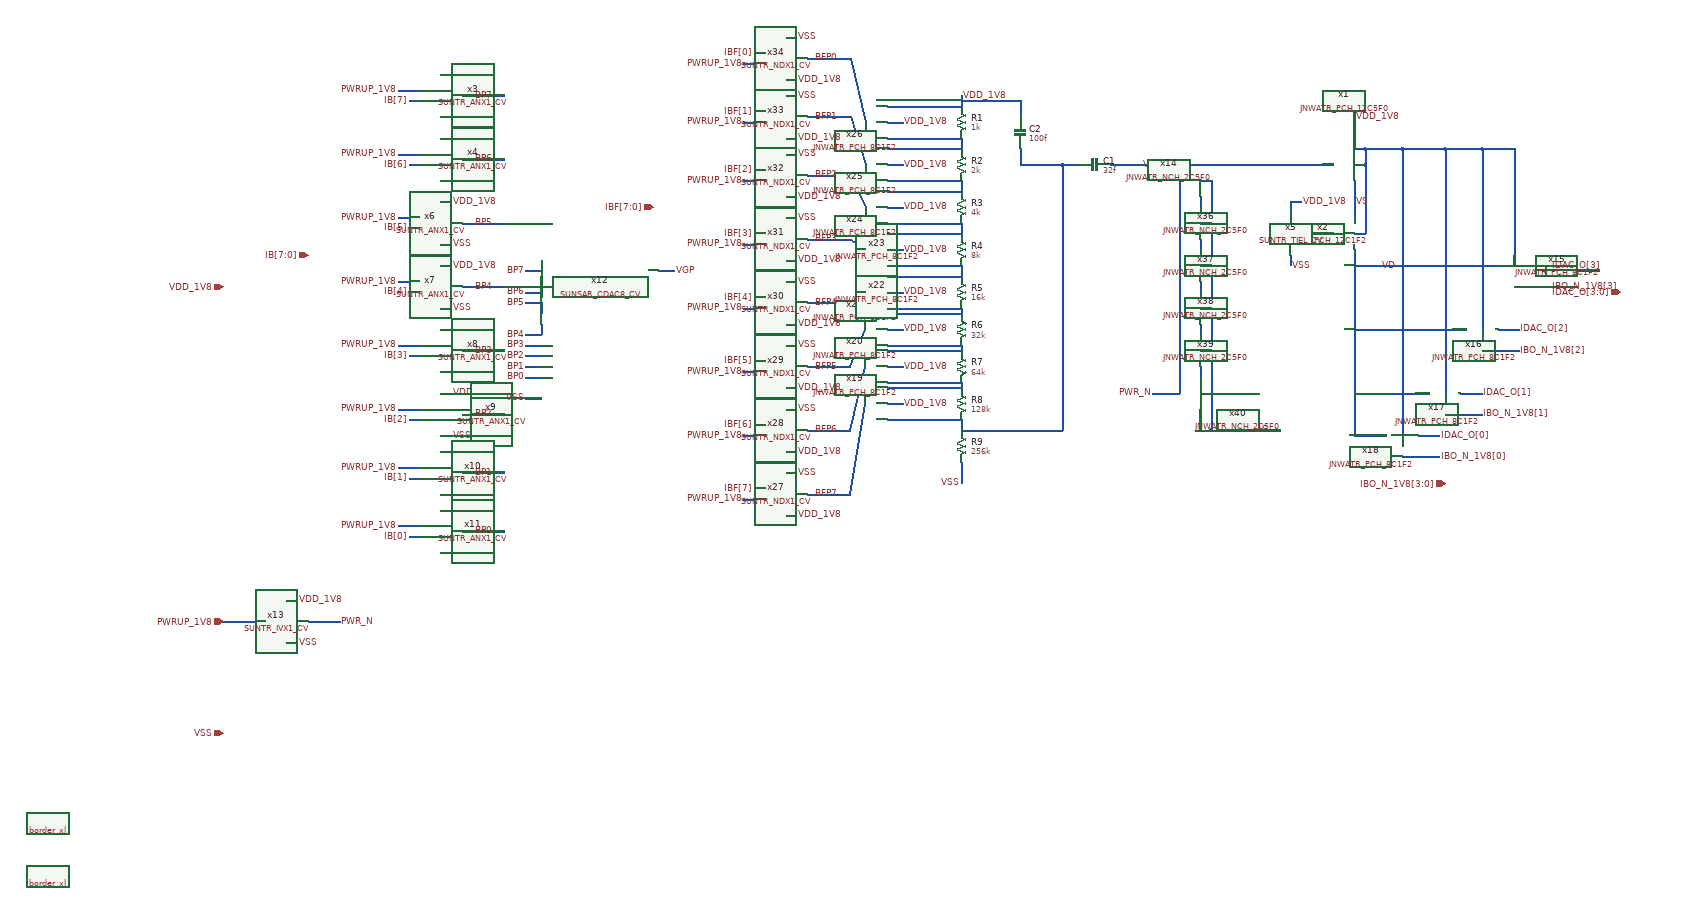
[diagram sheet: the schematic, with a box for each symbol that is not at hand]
v {xschem version=3.4.5 file_version=1.2
}
G {}
K {}
V {}
S {}
E {}
N 2300 -1210 2300 -1140 {
lab=VS}
N 2300 -1110 2320 -1110 {
lab=VDD_1V8}
N 2320 -1240 2320 -1110 {
lab=VDD_1V8}
N 2300 -1240 2320 -1240 {
lab=VDD_1V8}
N 2320 -1270 2320 -1240 {
lab=VDD_1V8}
N 2300 -1270 2320 -1270 {
lab=VDD_1V8}
N 2300 -1330 2300 -1270 {
lab=VDD_1V8}
N 1930 -1240 2260 -1240 {
lab=VGP}
N 580 -1410 600 -1410 {
lab=VDD_1V8}
N 580 -1330 600 -1330 {
lab=VSS}
N 520 -1360 540 -1360 {
lab=IB[7]}
N 580 -1290 600 -1290 {
lab=VDD_1V8}
N 580 -1210 600 -1210 {
lab=VSS}
N 520 -1240 540 -1240 {
lab=IB[6]}
N 580 -1170 600 -1170 {
lab=VDD_1V8}
N 580 -1090 600 -1090 {
lab=VSS}
N 520 -1120 540 -1120 {
lab=IB[5]}
N 580 -1050 600 -1050 {
lab=VDD_1V8}
N 580 -970 600 -970 {
lab=VSS}
N 520 -1000 540 -1000 {
lab=IB[4]}
N 580 -930 600 -930 {
lab=VDD_1V8}
N 580 -850 600 -850 {
lab=VSS}
N 520 -880 540 -880 {
lab=IB[3]}
N 580 -730 600 -730 {
lab=VSS}
N 520 -760 540 -760 {
lab=IB[2]}
N 580 -700 600 -700 {
lab=VDD_1V8}
N 580 -620 600 -620 {
lab=VSS}
N 520 -650 540 -650 {
lab=IB[1]}
N 580 -590 600 -590 {
lab=VDD_1V8}
N 580 -510 600 -510 {
lab=VSS}
N 520 -540 540 -540 {
lab=IB[0]}
N 620 -1370 700 -1370 {
lab=BP7}
N 620 -1250 700 -1250 {
lab=BP6}
N 620 -1130 700 -1130 {
lab=BP5}
N 620 -1010 700 -1010 {
lab=BP4}
N 620 -890 700 -890 {
lab=BP3}
N 620 -770 700 -770 {
lab=BP2}
N 620 -660 700 -660 {
lab=BP1}
N 620 -550 700 -550 {
lab=BP0}
N 1840 -1240 1930 -1240 {
lab=VGP}
N 2300 -1080 2300 -900 {
lab=VD}
N 290 -420 310 -420 {
lab=VDD_1V8}
N 290 -340 310 -340 {
lab=VSS}
N 230 -380 250 -380 {
lab=PWRUP_1V8}
N 170 -380 230 -380 {
lab=PWRUP_1V8}
N 330 -380 390 -380 {
lab=PWR_N}
N 2000 -740 2030 -740 {
lab=VSS}
N 2030 -740 2160 -740 {
lab=VSS}
N 2390 -1270 2390 -730 {
lab=VDD_1V8}
N 2320 -1270 2390 -1270 {
lab=VDD_1V8}
N 2470 -1270 2470 -810 {
lab=VDD_1V8}
N 2390 -1270 2470 -1270 {
lab=VDD_1V8}
N 2470 -1270 2540 -1270 {
lab=VDD_1V8}
N 2600 -1270 2600 -1050 {
lab=VDD_1V8}
N 2540 -1270 2600 -1270 {
lab=VDD_1V8}
N 2300 -1050 2570 -1050 {
lab=VD}
N 2300 -900 2300 -730 {
lab=VD}
N 2300 -730 2360 -730 {
lab=VD}
N 2300 -810 2440 -810 {
lab=VD}
N 2300 -930 2510 -930 {
lab=VD}
N 2540 -1270 2540 -930 {
lab=VDD_1V8}
N 2630 -1050 2670 -1050 {
lab=IDAC_O[3]}
N 2570 -930 2610 -930 {
lab=IDAC_O[2]}
N 2500 -810 2540 -810 {
lab=IDAC_O[1]}
N 2420 -730 2460 -730 {
lab=IDAC_O[0]}
N 2390 -690 2460 -690 {
lab=IBN_1V8[0]}
N 2470 -770 2540 -770 {
lab=IBN_1V8[1]}
N 2540 -890 2610 -890 {
lab=IBN_1V8[2]}
N 2600 -1010 2670 -1010 {
lab=IBN_1V8[3]}
N 580 -810 600 -810 {
lab=VDD_1V8}
N 500 -1380 540 -1380 {
lab=PWRUP_1V8}
N 500 -1260 540 -1260 {
lab=PWRUP_1V8}
N 500 -1140 540 -1140 {
lab=PWRUP_1V8}
N 500 -1020 540 -1020 {
lab=PWRUP_1V8}
N 500 -900 540 -900 {
lab=PWRUP_1V8}
N 500 -780 540 -780 {
lab=PWRUP_1V8}
N 500 -670 540 -670 {
lab=PWRUP_1V8}
N 500 -560 540 -560 {
lab=PWRUP_1V8}
N 740 -840 770 -840 {
lab=BP0}
N 740 -860 770 -860 {
lab=BP1}
N 740 -880 770 -880 {
lab=BP2}
N 740 -900 770 -900 {
lab=BP3}
N 740 -920 770 -920 {
lab=BP4}
N 740 -980 770 -980 {
lab=BP5}
N 740 -1000 770 -1000 {
lab=BP6}
N 770 -980 770 -960 {
lab=BP5}
N 740 -1040 770 -1040 {
lab=BP7}
N 770 -1020 770 -1000 {
lab=BP6}
N 990 -1040 1020 -1040 {
lab=VGP}
N 740 -800 770 -800 {
lab=VSS}
N 770 -1060 770 -1040 {
lab=BP7}
N 770 -940 770 -920 {
lab=BP4}
N 1560 -1290 1560 -1270 {
lab=#net2}
N 1560 -1210 1560 -1190 {
lab=#net3}
N 1560 -1130 1560 -1110 {
lab=#net4}
N 1560 -1050 1560 -1030 {
lab=#net5}
N 1560 -970 1560 -960 {
lab=#net6}
N 1560 -900 1560 -890 {
lab=#net7}
N 1560 -830 1560 -820 {
lab=#net8}
N 1560 -760 1560 -740 {
lab=#net9}
N 1750 -1240 1780 -1240 {
lab=#net9}
N 1750 -1240 1750 -740 {
lab=#net9}
N 1560 -740 1750 -740 {
lab=#net9}
N 1560 -680 1560 -640 {
lab=VSS}
N 1560 -1370 1560 -1350 {
lab=VDD_1V8}
N 1670 -1360 1670 -1330 {
lab=VDD_1V8}
N 1560 -1360 1670 -1360 {
lab=VDD_1V8}
N 1670 -1270 1670 -1240 {
lab=#net9}
N 1670 -1240 1750 -1240 {
lab=#net9}
N 1420 -790 1450 -790 {
lab=VDD_1V8}
N 1420 -820 1560 -820 {
lab=#net8}
N 1430 -760 1560 -760 {
lab=#net9}
N 1420 -760 1430 -760 {
lab=#net9}
N 1420 -860 1450 -860 {
lab=VDD_1V8}
N 1420 -890 1560 -890 {
lab=#net8}
N 1430 -830 1560 -830 {
lab=#net9}
N 1420 -830 1430 -830 {
lab=#net9}
N 1420 -930 1450 -930 {
lab=VDD_1V8}
N 1420 -960 1560 -960 {
lab=#net8}
N 1430 -900 1560 -900 {
lab=#net9}
N 1420 -900 1430 -900 {
lab=#net9}
N 1420 -1000 1450 -1000 {
lab=VDD_1V8}
N 1420 -1030 1560 -1030 {
lab=#net8}
N 1430 -970 1560 -970 {
lab=#net9}
N 1420 -970 1430 -970 {
lab=#net9}
N 1420 -1080 1450 -1080 {
lab=VDD_1V8}
N 1420 -1110 1560 -1110 {
lab=#net8}
N 1430 -1050 1560 -1050 {
lab=#net9}
N 1420 -1050 1430 -1050 {
lab=#net9}
N 1420 -1160 1450 -1160 {
lab=VDD_1V8}
N 1420 -1190 1560 -1190 {
lab=#net8}
N 1430 -1130 1560 -1130 {
lab=#net9}
N 1420 -1130 1430 -1130 {
lab=#net9}
N 1420 -1240 1450 -1240 {
lab=VDD_1V8}
N 1420 -1270 1560 -1270 {
lab=#net8}
N 1430 -1210 1560 -1210 {
lab=#net9}
N 1420 -1210 1430 -1210 {
lab=#net9}
N 1420 -1320 1450 -1320 {
lab=VDD_1V8}
N 1420 -1350 1560 -1350 {
lab=#net8}
N 1430 -1290 1560 -1290 {
lab=#net9}
N 1420 -1290 1430 -1290 {
lab=#net9}
N 1230 -580 1250 -580 {
lab=VDD_1V8}
N 1230 -660 1250 -660 {
lab=VSS}
N 1170 -630 1190 -630 {
lab=IB[7]}
N 1230 -700 1250 -700 {
lab=VDD_1V8}
N 1230 -780 1250 -780 {
lab=VSS}
N 1170 -750 1190 -750 {
lab=IB[6]}
N 1230 -820 1250 -820 {
lab=VDD_1V8}
N 1230 -900 1250 -900 {
lab=VSS}
N 1170 -870 1190 -870 {
lab=IB[5]}
N 1230 -940 1250 -940 {
lab=VDD_1V8}
N 1230 -1020 1250 -1020 {
lab=VSS}
N 1170 -990 1190 -990 {
lab=IB[4]}
N 1230 -1060 1250 -1060 {
lab=VDD_1V8}
N 1230 -1140 1250 -1140 {
lab=VSS}
N 1170 -1110 1190 -1110 {
lab=IB[3]}
N 1230 -1260 1250 -1260 {
lab=VSS}
N 1170 -1230 1190 -1230 {
lab=IB[2]}
N 1230 -1290 1250 -1290 {
lab=VDD_1V8}
N 1230 -1370 1250 -1370 {
lab=VSS}
N 1170 -1340 1190 -1340 {
lab=IB[1]}
N 1230 -1400 1250 -1400 {
lab=VDD_1V8}
N 1230 -1480 1250 -1480 {
lab=VSS}
N 1170 -1450 1190 -1450 {
lab=IB[0]}
N 1270 -620 1350 -620 {
lab=BP7}
N 1270 -740 1350 -740 {
lab=BP6}
N 1270 -860 1350 -860 {
lab=BP5}
N 1270 -980 1350 -980 {
lab=BP4}
N 1270 -1100 1350 -1100 {
lab=BP3}
N 1270 -1220 1350 -1220 {
lab=BP2}
N 1270 -1330 1350 -1330 {
lab=BP1}
N 1270 -1440 1350 -1440 {
lab=BP0}
N 1230 -1180 1250 -1180 {
lab=VDD_1V8}
N 1150 -610 1190 -610 {
lab=PWRUP_1V8}
N 1150 -730 1190 -730 {
lab=PWRUP_1V8}
N 1150 -850 1190 -850 {
lab=PWRUP_1V8}
N 1150 -970 1190 -970 {
lab=PWRUP_1V8}
N 1150 -1090 1190 -1090 {
lab=PWRUP_1V8}
N 1150 -1210 1190 -1210 {
lab=PWRUP_1V8}
N 1150 -1320 1190 -1320 {
lab=PWRUP_1V8}
N 1150 -1430 1190 -1430 {
lab=PWRUP_1V8}
N 1350 -1440 1380 -1320 {}
N 1350 -1330 1380 -1240 {}
N 1350 -1220 1380 -1160 {}
N 1350 -1100 1380 -1080 {}
N 1350 -980 1380 -1000 {}
N 1350 -860 1380 -930 {}
N 1350 -740 1380 -860 {}
N 1350 -620 1380 -790 {}
N 2660 -1040 2760 -1040 {}
N 2660 -1050 2660 -1040 {}
N 2300 -1340 2300 -1330 {}
N 2010 -780 2010 -740 {}
N 2010 -860 2010 -840 {}
N 2010 -940 2010 -920 {}
N 2010 -1020 2010 -1000 {}
N 2010 -1100 2010 -1080 {}
N 2010 -1180 2010 -1160 {}
N 2010 -1210 2030 -1210 {}
N 2030 -1210 2030 -740 {}
N 2010 -810 2030 -810 {}
N 2010 -890 2030 -890 {}
N 2010 -970 2030 -970 {}
N 2010 -1130 2030 -1130 {}
N 1970 -1210 1970 -810 {}
N 1920 -810 1970 -810 {}
N 2010 -1050 2030 -1050 {}
N 2220 -1110 2260 -1110 {}
N 2180 -1170 2180 -1150 {}
N 2180 -1170 2200 -1170 {}
N 2180 -1070 2180 -1050 {}
C {devices/ipin.sym} 170 -1010 0 0 {name=p1 lab=VDD_1V8}
C {devices/ipin.sym} 170 -170 0 0 {name=p2 lab=VSS}
C {devices/ipin.sym} 170 -380 0 0 {name=p3 lab=PWRUP_1V8}
C {JNW_ATR_SKY130NM/JNWATR_PCH_12C5F0.sym} 2260 -1240 0 0 {name=x1 }
C {JNW_ATR_SKY130NM/JNWATR_PCH_12C1F2.sym} 2260 -1110 0 0 {name=x2 }
C {devices/lab_wire.sym} 600 -1410 0 1 {name=p4 sig_type=std_logic lab=VDD_1V8}
C {devices/lab_wire.sym} 600 -1330 0 1 {name=p5 sig_type=std_logic lab=VSS}
C {devices/lab_wire.sym} 520 -1360 0 0 {name=p6 sig_type=std_logic lab=IB[7]}
C {devices/lab_wire.sym} 600 -1290 0 1 {name=p7 sig_type=std_logic lab=VDD_1V8}
C {devices/lab_wire.sym} 600 -1210 0 1 {name=p8 sig_type=std_logic lab=VSS}
C {devices/lab_wire.sym} 520 -1240 0 0 {name=p9 sig_type=std_logic lab=IB[6]}
C {devices/lab_wire.sym} 600 -1170 0 1 {name=p10 sig_type=std_logic lab=VDD_1V8}
C {devices/lab_wire.sym} 600 -1090 0 1 {name=p11 sig_type=std_logic lab=VSS}
C {devices/lab_wire.sym} 520 -1120 0 0 {name=p12 sig_type=std_logic lab=IB[5]}
C {devices/lab_wire.sym} 600 -1050 0 1 {name=p13 sig_type=std_logic lab=VDD_1V8}
C {devices/lab_wire.sym} 600 -970 0 1 {name=p14 sig_type=std_logic lab=VSS}
C {devices/lab_wire.sym} 520 -1000 0 0 {name=p15 sig_type=std_logic lab=IB[4]}
C {devices/lab_wire.sym} 600 -930 0 1 {name=p16 sig_type=std_logic lab=VDD_1V8}
C {devices/lab_wire.sym} 600 -850 0 1 {name=p17 sig_type=std_logic lab=VSS}
C {devices/lab_wire.sym} 520 -880 0 0 {name=p18 sig_type=std_logic lab=IB[3]}
C {devices/lab_wire.sym} 600 -810 0 1 {name=p19 sig_type=std_logic lab=VDD_1V8}
C {devices/lab_wire.sym} 600 -730 0 1 {name=p20 sig_type=std_logic lab=VSS}
C {devices/lab_wire.sym} 520 -760 0 0 {name=p21 sig_type=std_logic lab=IB[2]}
C {devices/lab_wire.sym} 600 -700 0 1 {name=p22 sig_type=std_logic lab=VDD_1V8}
C {devices/lab_wire.sym} 600 -620 0 1 {name=p23 sig_type=std_logic lab=VSS}
C {devices/lab_wire.sym} 520 -650 0 0 {name=p24 sig_type=std_logic lab=IB[1]}
C {devices/lab_wire.sym} 600 -590 0 1 {name=p25 sig_type=std_logic lab=VDD_1V8}
C {devices/lab_wire.sym} 600 -510 0 1 {name=p26 sig_type=std_logic lab=VSS}
C {devices/lab_wire.sym} 520 -540 0 0 {name=p27 sig_type=std_logic lab=IB[0]}
C {devices/lab_wire.sym} 2300 -1330 0 1 {name=p28 sig_type=std_logic lab=VDD_1V8}
C {SUN_TR_SKY130NM/SUNTR_IVX1_CV.sym} 250 -380 0 0 {name=x13 }
C {devices/lab_wire.sym} 310 -420 0 1 {name=p29 sig_type=std_logic lab=VDD_1V8}
C {devices/lab_wire.sym} 310 -340 0 1 {name=p30 sig_type=std_logic lab=VSS}
C {devices/lab_wire.sym} 2100 -740 0 1 {name=p31 sig_type=std_logic lab=VSS}
C {devices/lab_wire.sym} 390 -380 0 1 {name=p33 sig_type=std_logic lab=PWR_N}
C {devices/iopin.sym} 2800 -1000 0 0 {name=p35 lab=IDAC_O[3:0]}
C {JNW_ATR_SKY130NM/JNWATR_PCH_8C1F2.sym} 2600 -1010 3 0 {name=x15 }
C {JNW_ATR_SKY130NM/JNWATR_PCH_8C1F2.sym} 2540 -890 3 0 {name=x16 }
C {JNW_ATR_SKY130NM/JNWATR_PCH_8C1F2.sym} 2470 -770 3 0 {name=x17 }
C {JNW_ATR_SKY130NM/JNWATR_PCH_8C1F2.sym} 2390 -690 3 0 {name=x18 }
C {devices/lab_wire.sym} 2460 -730 0 1 {name=p36 sig_type=std_logic lab=IDAC_O[0]}
C {devices/lab_wire.sym} 2540 -810 0 1 {name=p37 sig_type=std_logic lab=IDAC_O[1]}
C {devices/lab_wire.sym} 2610 -930 0 1 {name=p38 sig_type=std_logic lab=IDAC_O[2]}
C {devices/lab_wire.sym} 2670 -1050 0 1 {name=p39 sig_type=std_logic lab=IDAC_O[3]}
C {devices/lab_wire.sym} 2460 -690 0 1 {name=p40 sig_type=std_logic lab=IBO_N_1V8[0]}
C {devices/lab_wire.sym} 2540 -770 0 1 {name=p41 sig_type=std_logic lab=IBO_N_1V8[1]}
C {devices/lab_wire.sym} 2610 -890 0 1 {name=p42 sig_type=std_logic lab=IBO_N_1V8[2]}
C {devices/lab_wire.sym} 2670 -1010 0 1 {name=p43 sig_type=std_logic lab=IBO_N_1V8[3]}
C {devices/ipin.sym} 330 -1070 0 0 {name=p44 lab=IB[7:0]}
C {devices/ipin.sym} 2470 -640 0 0 {name=p45 lab=IBO_N_1V8[3:0]}
C {devices/lab_wire.sym} 2300 -1170 0 1 {name=p47 sig_type=std_logic lab=VS}
C {devices/lab_wire.sym} 2350 -1050 0 1 {name=p48 sig_type=std_logic lab=VD}
C {devices/lab_wire.sym} 1900 -1240 0 1 {name=p49 sig_type=std_logic lab=VGP}
C {SUN_TR_SKY130NM/SUNTR_ANX1_CV.sym} 540 -1360 0 0 {name=x3 }
C {SUN_TR_SKY130NM/SUNTR_ANX1_CV.sym} 540 -1240 0 0 {name=x4 }
C {SUN_TR_SKY130NM/SUNTR_ANX1_CV.sym} 540 -1120 0 0 {name=x6 }
C {SUN_TR_SKY130NM/SUNTR_ANX1_CV.sym} 540 -1000 0 0 {name=x7 }
C {SUN_TR_SKY130NM/SUNTR_ANX1_CV.sym} 540 -880 0 0 {name=x8 }
C {SUN_TR_SKY130NM/SUNTR_ANX1_CV.sym} 540 -760 0 0 {name=x9 }
C {SUN_TR_SKY130NM/SUNTR_ANX1_CV.sym} 540 -650 0 0 {name=x10 }
C {SUN_TR_SKY130NM/SUNTR_ANX1_CV.sym} 540 -540 0 0 {name=x11 }
C {devices/lab_wire.sym} 500 -1380 0 0 {name=p50 sig_type=std_logic lab=PWRUP_1V8}
C {devices/lab_wire.sym} 500 -1260 0 0 {name=p51 sig_type=std_logic lab=PWRUP_1V8}
C {devices/lab_wire.sym} 500 -1140 0 0 {name=p52 sig_type=std_logic lab=PWRUP_1V8}
C {devices/lab_wire.sym} 500 -1020 0 0 {name=p53 sig_type=std_logic lab=PWRUP_1V8}
C {devices/lab_wire.sym} 500 -900 0 0 {name=p54 sig_type=std_logic lab=PWRUP_1V8}
C {devices/lab_wire.sym} 500 -780 0 0 {name=p55 sig_type=std_logic lab=PWRUP_1V8}
C {devices/lab_wire.sym} 500 -670 0 0 {name=p56 sig_type=std_logic lab=PWRUP_1V8}
C {devices/lab_wire.sym} 500 -560 0 0 {name=p57 sig_type=std_logic lab=PWRUP_1V8}
C {devices/lab_wire.sym} 680 -1370 0 0 {name=p58 sig_type=std_logic lab=BP7
}
C {devices/lab_wire.sym} 680 -1250 0 0 {name=p59 sig_type=std_logic lab=BP6
}
C {devices/lab_wire.sym} 680 -1130 0 0 {name=p60 sig_type=std_logic lab=BP5
}
C {devices/lab_wire.sym} 680 -1010 0 0 {name=p61 sig_type=std_logic lab=BP4
}
C {devices/lab_wire.sym} 680 -890 0 0 {name=p62 sig_type=std_logic lab=BP3
}
C {devices/lab_wire.sym} 680 -770 0 0 {name=p63 sig_type=std_logic lab=BP2
}
C {devices/lab_wire.sym} 680 -660 0 0 {name=p64 sig_type=std_logic lab=BP1
}
C {devices/lab_wire.sym} 680 -550 0 0 {name=p65 sig_type=std_logic lab=BP0
}
C {devices/lab_wire.sym} 740 -840 0 0 {name=p46 sig_type=std_logic lab=BP0
}
C {devices/lab_wire.sym} 740 -860 0 0 {name=p66 sig_type=std_logic lab=BP1
}
C {devices/lab_wire.sym} 740 -880 0 0 {name=p67 sig_type=std_logic lab=BP2
}
C {devices/lab_wire.sym} 740 -900 0 0 {name=p68 sig_type=std_logic lab=BP3
}
C {devices/lab_wire.sym} 740 -920 0 0 {name=p69 sig_type=std_logic lab=BP4
}
C {devices/lab_wire.sym} 740 -980 0 0 {name=p70 sig_type=std_logic lab=BP5
}
C {devices/lab_wire.sym} 740 -1000 0 0 {name=p71 sig_type=std_logic lab=BP6
}
C {devices/lab_wire.sym} 740 -1040 0 0 {name=p72 sig_type=std_logic lab=BP7
}
C {devices/lab_wire.sym} 1020 -1040 0 1 {name=p73 sig_type=std_logic lab=VGP
}
C {devices/lab_wire.sym} 740 -800 0 0 {name=p74 sig_type=std_logic lab=VSS
}
C {SUN_SAR9B_SKY130NM/SUNSAR_CDAC8_CV.sym} 790 -1060 0 0 {name=x12}
C {devices/res.sym} 1560 -1320 0 0 {name=R1
value=1k
footprint=1206
device=resistor
m=1}
C {devices/res.sym} 1560 -1240 0 0 {name=R2
value=2k
footprint=1206
device=resistor
m=1}
C {devices/res.sym} 1560 -1160 0 0 {name=R3
value=4k
footprint=1206
device=resistor
m=1}
C {devices/res.sym} 1560 -1080 0 0 {name=R4
value=8k
footprint=1206
device=resistor
m=1}
C {devices/res.sym} 1560 -1000 0 0 {name=R5
value=16k
footprint=1206
device=resistor
m=1}
C {devices/res.sym} 1560 -930 0 0 {name=R6
value=32k
footprint=1206
device=resistor
m=1}
C {devices/res.sym} 1560 -860 0 0 {name=R7
value=64k
footprint=1206
device=resistor
m=1}
C {devices/res.sym} 1560 -790 0 0 {name=R8
value=128k
footprint=1206
device=resistor
m=1}
C {devices/res.sym} 1560 -710 0 0 {name=R9
value=256k
footprint=1206
device=resistor
m=1}
C {devices/lab_wire.sym} 1560 -640 0 0 {name=p32 sig_type=std_logic lab=VSS}
C {devices/lab_wire.sym} 1560 -1370 0 1 {name=p75 sig_type=std_logic lab=VDD_1V8}
C {devices/capa.sym} 1670 -1300 0 0 {name=C2
m=1
value=100f
footprint=1206
device="ceramic capacitor"}
C {JNW_ATR_SKY130NM/JNWATR_PCH_8C1F2.sym} 1380 -790 0 0 {name=x19 }
C {devices/lab_wire.sym} 1450 -790 0 1 {name=p76 sig_type=std_logic lab=VDD_1V8}
C {JNW_ATR_SKY130NM/JNWATR_PCH_8C1F2.sym} 1380 -860 0 0 {name=x20 }
C {devices/lab_wire.sym} 1450 -860 0 1 {name=p77 sig_type=std_logic lab=VDD_1V8}
C {JNW_ATR_SKY130NM/JNWATR_PCH_8C1F2.sym} 1380 -930 0 0 {name=x21 }
C {devices/lab_wire.sym} 1450 -930 0 1 {name=p78 sig_type=std_logic lab=VDD_1V8}
C {JNW_ATR_SKY130NM/JNWATR_PCH_8C1F2.sym} 1380 -1000 0 0 {name=x22 }
C {devices/lab_wire.sym} 1450 -1000 0 1 {name=p79 sig_type=std_logic lab=VDD_1V8}
C {JNW_ATR_SKY130NM/JNWATR_PCH_8C1F2.sym} 1380 -1080 0 0 {name=x23 }
C {devices/lab_wire.sym} 1450 -1080 0 1 {name=p80 sig_type=std_logic lab=VDD_1V8}
C {JNW_ATR_SKY130NM/JNWATR_PCH_8C1F2.sym} 1380 -1160 0 0 {name=x24 }
C {devices/lab_wire.sym} 1450 -1160 0 1 {name=p81 sig_type=std_logic lab=VDD_1V8}
C {JNW_ATR_SKY130NM/JNWATR_PCH_8C1F2.sym} 1380 -1240 0 0 {name=x25 }
C {devices/lab_wire.sym} 1450 -1240 0 1 {name=p82 sig_type=std_logic lab=VDD_1V8}
C {JNW_ATR_SKY130NM/JNWATR_PCH_8C1F2.sym} 1380 -1320 0 0 {name=x26 }
C {devices/lab_wire.sym} 1450 -1320 0 1 {name=p83 sig_type=std_logic lab=VDD_1V8}
C {devices/lab_wire.sym} 1250 -580 2 0 {name=p84 sig_type=std_logic lab=VDD_1V8}
C {devices/lab_wire.sym} 1250 -660 2 0 {name=p85 sig_type=std_logic lab=VSS}
C {devices/lab_wire.sym} 1170 -630 2 1 {name=p86 sig_type=std_logic lab=IBF[7]}
C {devices/lab_wire.sym} 1250 -700 2 0 {name=p87 sig_type=std_logic lab=VDD_1V8}
C {devices/lab_wire.sym} 1250 -780 2 0 {name=p88 sig_type=std_logic lab=VSS}
C {devices/lab_wire.sym} 1170 -750 2 1 {name=p89 sig_type=std_logic lab=IBF[6]}
C {devices/lab_wire.sym} 1250 -820 2 0 {name=p90 sig_type=std_logic lab=VDD_1V8}
C {devices/lab_wire.sym} 1250 -900 2 0 {name=p91 sig_type=std_logic lab=VSS}
C {devices/lab_wire.sym} 1170 -870 2 1 {name=p92 sig_type=std_logic lab=IBF[5]}
C {devices/lab_wire.sym} 1250 -940 2 0 {name=p93 sig_type=std_logic lab=VDD_1V8}
C {devices/lab_wire.sym} 1250 -1020 2 0 {name=p94 sig_type=std_logic lab=VSS}
C {devices/lab_wire.sym} 1170 -990 2 1 {name=p95 sig_type=std_logic lab=IBF[4]}
C {devices/lab_wire.sym} 1250 -1060 2 0 {name=p96 sig_type=std_logic lab=VDD_1V8}
C {devices/lab_wire.sym} 1250 -1140 2 0 {name=p97 sig_type=std_logic lab=VSS}
C {devices/lab_wire.sym} 1170 -1110 2 1 {name=p98 sig_type=std_logic lab=IBF[3]}
C {devices/lab_wire.sym} 1250 -1180 2 0 {name=p99 sig_type=std_logic lab=VDD_1V8}
C {devices/lab_wire.sym} 1250 -1260 2 0 {name=p100 sig_type=std_logic lab=VSS}
C {devices/lab_wire.sym} 1170 -1230 2 1 {name=p101 sig_type=std_logic lab=IBF[2]}
C {devices/lab_wire.sym} 1250 -1290 2 0 {name=p102 sig_type=std_logic lab=VDD_1V8}
C {devices/lab_wire.sym} 1250 -1370 2 0 {name=p103 sig_type=std_logic lab=VSS}
C {devices/lab_wire.sym} 1170 -1340 2 1 {name=p104 sig_type=std_logic lab=IBF[1]}
C {devices/lab_wire.sym} 1250 -1400 2 0 {name=p105 sig_type=std_logic lab=VDD_1V8}
C {devices/lab_wire.sym} 1250 -1480 2 0 {name=p106 sig_type=std_logic lab=VSS}
C {devices/lab_wire.sym} 1170 -1450 2 1 {name=p107 sig_type=std_logic lab=IBF[0]}
C {SUN_TR_SKY130NM/SUNTR_NDX1_CV.sym} 1190 -630 2 1 {name=x27 }
C {SUN_TR_SKY130NM/SUNTR_NDX1_CV.sym} 1190 -750 2 1 {name=x28 }
C {SUN_TR_SKY130NM/SUNTR_NDX1_CV.sym} 1190 -870 2 1 {name=x29 }
C {SUN_TR_SKY130NM/SUNTR_NDX1_CV.sym} 1190 -990 2 1 {name=x30 }
C {SUN_TR_SKY130NM/SUNTR_NDX1_CV.sym} 1190 -1110 2 1 {name=x31 }
C {SUN_TR_SKY130NM/SUNTR_NDX1_CV.sym} 1190 -1230 2 1 {name=x32 }
C {SUN_TR_SKY130NM/SUNTR_NDX1_CV.sym} 1190 -1340 2 1 {name=x33 }
C {SUN_TR_SKY130NM/SUNTR_NDX1_CV.sym} 1190 -1450 2 1 {name=x34 }
C {devices/lab_wire.sym} 1150 -610 2 1 {name=p108 sig_type=std_logic lab=PWRUP_1V8}
C {devices/lab_wire.sym} 1150 -730 2 1 {name=p109 sig_type=std_logic lab=PWRUP_1V8}
C {devices/lab_wire.sym} 1150 -850 2 1 {name=p110 sig_type=std_logic lab=PWRUP_1V8}
C {devices/lab_wire.sym} 1150 -970 2 1 {name=p111 sig_type=std_logic lab=PWRUP_1V8}
C {devices/lab_wire.sym} 1150 -1090 2 1 {name=p112 sig_type=std_logic lab=PWRUP_1V8}
C {devices/lab_wire.sym} 1150 -1210 2 1 {name=p113 sig_type=std_logic lab=PWRUP_1V8}
C {devices/lab_wire.sym} 1150 -1320 2 1 {name=p114 sig_type=std_logic lab=PWRUP_1V8}
C {devices/lab_wire.sym} 1150 -1430 2 1 {name=p115 sig_type=std_logic lab=PWRUP_1V8}
C {devices/lab_wire.sym} 1330 -620 2 1 {name=p116 sig_type=std_logic lab=BFP7
}
C {devices/lab_wire.sym} 1330 -740 2 1 {name=p117 sig_type=std_logic lab=BFP6
}
C {devices/lab_wire.sym} 1330 -860 2 1 {name=p118 sig_type=std_logic lab=BFP5
}
C {devices/lab_wire.sym} 1330 -980 2 1 {name=p119 sig_type=std_logic lab=BFP4
}
C {devices/lab_wire.sym} 1330 -1100 2 1 {name=p120 sig_type=std_logic lab=BFP3
}
C {devices/lab_wire.sym} 1330 -1220 2 1 {name=p121 sig_type=std_logic lab=BFP2
}
C {devices/lab_wire.sym} 1330 -1330 2 1 {name=p122 sig_type=std_logic lab=BFP1
}
C {devices/lab_wire.sym} 1330 -1440 2 1 {name=p123 sig_type=std_logic lab=BFP0
}
C {devices/ipin.sym} 980 -1160 0 0 {name=p124 lab=IBF[7:0]}
C {devices/lab_wire.sym} 1920 -810 0 0 {name=p34 sig_type=std_logic lab=PWR_N}
C {JNW_ATR_SKY130NM/JNWATR_NCH_2C5F0.sym} 1970 -1210 0 0 {name=x14 }
C {JNW_ATR_SKY130NM/JNWATR_NCH_2C5F0.sym} 1970 -1130 0 0 {name=x36 }
C {JNW_ATR_SKY130NM/JNWATR_NCH_2C5F0.sym} 1970 -1050 0 0 {name=x37 }
C {JNW_ATR_SKY130NM/JNWATR_NCH_2C5F0.sym} 1970 -970 0 0 {name=x38 }
C {JNW_ATR_SKY130NM/JNWATR_NCH_2C5F0.sym} 1970 -890 0 0 {name=x39 }
C {JNW_ATR_SKY130NM/JNWATR_NCH_2C5F0.sym} 1970 -810 0 0 {name=x40 }
C {devices/capa.sym} 1810 -1240 1 0 {name=C1
m=1
value=32f
footprint=1206
device="ceramic capacitor"}
C {cborder/border_xl.sym} -160 0 0 0 {}
C {SUN_TR_SKY130NM/SUNTR_TIEL_CV.sym} 2180 -1070 0 0 {name=x5 }
C {devices/lab_wire.sym} 2200 -1170 0 1 {name=p125 sig_type=std_logic lab=VDD_1V8}
C {cborder/border_xl.sym} -160 100 0 0 {}
C {devices/lab_wire.sym} 2180 -1050 0 1 {name=p126 sig_type=std_logic lab=VSS}
